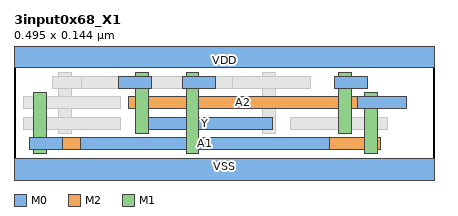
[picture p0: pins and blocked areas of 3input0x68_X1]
MACRO 3input0x68_X1
  CLASS CORE ;
  ORIGIN 0 0 ;
  FOREIGN 3input0x68_X1 0 0 ;
  SIZE 0.4950 BY 0.1440 ;
  SYMMETRY X Y ;
  SITE coresite ;
  PIN A1
    DIRECTION INPUT ;
    USE SIGNAL ;
    PORT
      LAYER M0 ;
        RECT 0.0780 0.0290 0.3720 0.0430 ;
    END
  END A1
  PIN A2
    DIRECTION INPUT ;
    USE SIGNAL ;
    PORT
      LAYER M2 ;
        RECT 0.1350 0.0770 0.4050 0.0910 ;
      LAYER M1 ;
        RECT 0.1430 0.0480 0.1580 0.1200 ;
        RECT 0.3830 0.0480 0.3980 0.1200 ;
      LAYER M0 ;
        RECT 0.3780 0.1010 0.4170 0.1150 ;
        RECT 0.1230 0.1010 0.1620 0.1150 ;
    END
  END A2
  PIN A3
    DIRECTION INPUT ;
    USE SIGNAL ;
    PORT
      LAYER M2 ;
        RECT 0.0180 0.0290 0.4320 0.0430 ;
      LAYER M1 ;
        RECT 0.0230 0.0240 0.0380 0.0960 ;
        RECT 0.2030 0.0240 0.2180 0.1200 ;
        RECT 0.4130 0.0240 0.4280 0.0960 ;
      LAYER M0 ;
        RECT 0.4050 0.0770 0.4620 0.0910 ;
        RECT 0.1980 0.1010 0.2370 0.1150 ;
        RECT 0.0180 0.0290 0.0570 0.0430 ;
    END
  END A3
  PIN Y
    DIRECTION OUTPUT ;
    USE SIGNAL ;
    PORT
      LAYER M0 ;
        RECT 0.1460 0.0530 0.3050 0.0670 ;
    END
  END Y
  PIN VDD
    DIRECTION INOUT ;
    USE POWER ;
    SHAPE ABUTMENT ;
    PORT
      LAYER M0 ;
        RECT 0.0000 0.1260 0.4950 0.1620 ;
    END
  END VDD
  PIN VSS
    DIRECTION INOUT ;
    USE GROUND ;
    SHAPE ABUTMENT ;
    PORT
      LAYER M0 ;
        RECT 0.0000 -0.0180 0.4950 0.0180 ;
    END
  END VSS
  OBS
    LAYER M2 ;
      RECT 0.0450 0.1010 0.3150 0.1150 ;
    LAYER V1 ;
      RECT 0.0230 0.0290 0.0370 0.0430 ;
      RECT 0.2030 0.0290 0.2170 0.0430 ;
      RECT 0.4130 0.0290 0.4270 0.0430 ;
      RECT 0.1430 0.0770 0.1570 0.0910 ;
      RECT 0.3830 0.0770 0.3970 0.0910 ;
      RECT 0.0530 0.1010 0.0670 0.1150 ;
      RECT 0.2930 0.1010 0.3070 0.1150 ;
    LAYER M1 ;
      RECT 0.0530 0.0480 0.0680 0.1200 ;
      RECT 0.2930 0.0480 0.3080 0.1200 ;
    LAYER V0 ;
      RECT 0.0230 0.0290 0.0370 0.0430 ;
      RECT 0.2030 0.1010 0.2170 0.1150 ;
      RECT 0.4130 0.0770 0.4270 0.0910 ;
      RECT 0.1430 0.1010 0.1570 0.1150 ;
      RECT 0.3830 0.1010 0.3970 0.1150 ;
      RECT 0.0530 0.1010 0.0670 0.1150 ;
      RECT 0.2930 0.0770 0.3070 0.0910 ;
    LAYER M0 ;
      RECT 0.0110 0.0530 0.1250 0.0670 ;
      RECT 0.3260 0.0530 0.4400 0.0670 ;
      RECT 0.0110 0.0770 0.1250 0.0910 ;
      RECT 0.2360 0.0770 0.3150 0.0910 ;
      RECT 0.0450 0.1010 0.0800 0.1150 ;
      RECT 0.2580 0.1010 0.3500 0.1150 ;
  END
END 3input0x68_X1
